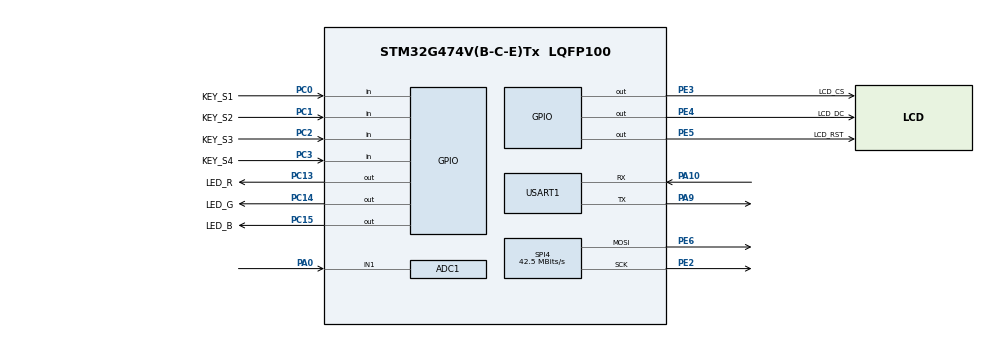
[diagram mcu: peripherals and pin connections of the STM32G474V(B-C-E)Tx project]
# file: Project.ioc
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ADC1.Channel-0\#ChannelRegularConversion=ADC_CHANNEL_1
ADC1.ContinuousConvMode=ENABLE
ADC1.NbrOfConversionFlag=1
ADC1.OffsetNumber-0\#ChannelRegularConversion=ADC_OFFSET_NONE
ADC1.Overrun=ADC_OVR_DATA_OVERWRITTEN
ADC1.Rank-0\#ChannelRegularConversion=1
ADC1.SamplingTime-0\#ChannelRegularConversion=ADC_SAMPLETIME_2CYCLES_5
ADC1.master=1
Dma.Request0=USART1_TX
Dma.Request1=USART1_RX
Dma.USART1_RX.1.Direction=DMA_PERIPH_TO_MEMORY
Dma.USART1_RX.1.EventEnable=DISABLE
Dma.USART1_RX.1.Instance=DMA1_Channel2
Dma.USART1_RX.1.MemDataAlignment=DMA_MDATAALIGN_BYTE
Dma.USART1_RX.1.MemInc=DMA_MINC_ENABLE
Dma.USART1_RX.1.Mode=DMA_NORMAL
Dma.USART1_RX.1.PeriphDataAlignment=DMA_PDATAALIGN_BYTE
Dma.USART1_RX.1.PeriphInc=DMA_PINC_DISABLE
Dma.USART1_RX.1.Polarity=HAL_DMAMUX_REQ_GEN_RISING
Dma.USART1_RX.1.Priority=DMA_PRIORITY_LOW
Dma.USART1_RX.1.RequestNumber=1
Dma.USART1_RX.1.SignalID=NONE
Dma.USART1_RX.1.SyncEnable=DISABLE
Dma.USART1_RX.1.SyncPolarity=HAL_DMAMUX_SYNC_NO_EVENT
Dma.USART1_RX.1.SyncRequestNumber=1
Dma.USART1_RX.1.SyncSignalID=NONE
Dma.USART1_TX.0.Direction=DMA_MEMORY_TO_PERIPH
Dma.USART1_TX.0.EventEnable=DISABLE
Dma.USART1_TX.0.Instance=DMA1_Channel1
Dma.USART1_TX.0.MemDataAlignment=DMA_MDATAALIGN_BYTE
Dma.USART1_TX.0.MemInc=DMA_MINC_ENABLE
Dma.USART1_TX.0.Mode=DMA_NORMAL
Dma.USART1_TX.0.PeriphDataAlignment=DMA_PDATAALIGN_BYTE
Dma.USART1_TX.0.PeriphInc=DMA_PINC_DISABLE
Dma.USART1_TX.0.Polarity=HAL_DMAMUX_REQ_GEN_RISING
Dma.USART1_TX.0.Priority=DMA_PRIORITY_LOW
Dma.USART1_TX.0.RequestNumber=1
Dma.USART1_TX.0.SignalID=NONE
Dma.USART1_TX.0.SyncEnable=DISABLE
Dma.USART1_TX.0.SyncPolarity=HAL_DMAMUX_SYNC_NO_EVENT
Dma.USART1_TX.0.SyncRequestNumber=1
Dma.USART1_TX.0.SyncSignalID=NONE
Mcu.Family=STM32G4
Mcu.Name=STM32G474V(B-C-E)Tx
Mcu.Package=LQFP100
NVIC.DMA1_Channel1_IRQn=true\:0\:0\:false\:false\:true\:false\:true\:true
NVIC.DMA1_Channel2_IRQn=true\:0\:0\:false\:false\:true\:false\:true\:true
NVIC.PriorityGroup=NVIC_PRIORITYGROUP_4
NVIC.TIM1_TRG_COM_TIM17_IRQn=true\:1\:0\:true\:false\:true\:true\:true\:true
NVIC.USART1_IRQn=true\:0\:0\:false\:false\:true\:false\:true\:true
PA0.Mode=IN1-Single-Ended
PA0.Signal=ADC1_IN1
PA10.Mode=Asynchronous
PA10.Signal=USART1_RX
PA13.Mode=Serial_Wire
PA13.Signal=SYS_JTMS-SWDIO
PA14.Mode=Serial_Wire
PA14.Signal=SYS_JTCK-SWCLK
PA9.Mode=Asynchronous
PA9.Signal=USART1_TX
PC0.GPIO_Label=KEY_S1
PC0.Signal=GPIO_Input
PC1.GPIO_Label=KEY_S2
PC1.Signal=GPIO_Input
PC13.GPIO_Label=LED_R
PC13.PinState=GPIO_PIN_SET
PC13.Signal=GPIO_Output
PC14-OSC32_IN.GPIO_Label=LED_G
PC14-OSC32_IN.PinState=GPIO_PIN_SET
PC14-OSC32_IN.Signal=GPIO_Output
PC15-OSC32_OUT.GPIO_Label=LED_B
PC15-OSC32_OUT.PinState=GPIO_PIN_SET
PC15-OSC32_OUT.Signal=GPIO_Output
PC2.GPIO_Label=KEY_S3
PC2.Signal=GPIO_Input
PC3.GPIO_Label=KEY_S4
PC3.Signal=GPIO_Input
PE2.GPIO_Speed=GPIO_SPEED_FREQ_VERY_HIGH
PE2.Mode=TX_Only_Simplex_Unidirect_Master
PE2.Signal=SPI4_SCK
PE3.GPIO_Label=LCD_CS
PE3.PinState=GPIO_PIN_SET
PE3.Signal=GPIO_Output
PE4.GPIO_Label=LCD_DC
PE4.PinState=GPIO_PIN_SET
PE4.Signal=GPIO_Output
PE5.GPIO_Label=LCD_RST
PE5.Signal=GPIO_Output
PE6.GPIO_Speed=GPIO_SPEED_FREQ_VERY_HIGH
PE6.Mode=TX_Only_Simplex_Unidirect_Master
PE6.Signal=SPI4_MOSI
PF0-OSC_IN.Mode=HSE-External-Oscillator
PF0-OSC_IN.Signal=RCC_OSC_IN
PF1-OSC_OUT.Mode=HSE-External-Oscillator
PF1-OSC_OUT.Signal=RCC_OSC_OUT
ProjectManager.HeapSize=0x0
ProjectManager.StackSize=0x1000
ProjectManager.TargetToolchain=MDK-ARM V5.32
RCC.ADC12Freq_Value=170000000
RCC.ADC345Freq_Value=170000000
RCC.AHBFreq_Value=170000000
RCC.APB1Freq_Value=170000000
RCC.APB1TimFreq_Value=170000000
RCC.APB2Freq_Value=170000000
RCC.APB2TimFreq_Value=170000000
RCC.CortexFreq_Value=170000000
RCC.EXTERNAL_CLOCK_VALUE=12288000
RCC.HCLKFreq_Value=170000000
RCC.HSE_VALUE=24000000
RCC.HSI48_VALUE=48000000
RCC.HSI_VALUE=16000000
RCC.LSE_VALUE=32768
RCC.PLLM=RCC_PLLM_DIV6
RCC.PLLN=85
RCC.PLLSourceVirtual=RCC_PLLSOURCE_HSE
RCC.SYSCLKFreq_VALUE=170000000
RCC.SYSCLKSource=RCC_SYSCLKSOURCE_PLLCLK
RCC.USBFreq_Value=170000000
RCC.VCOOutputFreq_Value=340000000
SPI4.BaudRatePrescaler=SPI_BAUDRATEPRESCALER_4
SPI4.CalculateBaudRate=42.5 MBits/s
SPI4.DataSize=SPI_DATASIZE_8BIT
SPI4.Direction=SPI_DIRECTION_2LINES
SPI4.Mode=SPI_MODE_MASTER
SPI4.VirtualType=VM_MASTER
TIM17.PeriodNoDither=9999
TIM17.Prescaler=199
USART1.VirtualMode-Asynchronous=VM_ASYNC
VP_SYS_VS_DBSignals.Mode=DisableDeadBatterySignals
VP_TIM17_VS_ClockSourceINT.Mode=Enable_Timer
board=custom

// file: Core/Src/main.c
/* USER CODE BEGIN Header */
/**
  ******************************************************************************
  * @file           : main.c
  * @brief          : Main program body
  ******************************************************************************
  * @attention
  *
  * Copyright (c) 2026 STMicroelectronics.
  * All rights reserved.
  *
  * This software is licensed under terms that can be found in the LICENSE file
  * in the root directory of this software component.
  * If no LICENSE file comes with this software, it is provided AS-IS.
  *
  ******************************************************************************
  */
/* USER CODE END Header */
#include "main.h"
#include "adc.h"
#include "dma.h"
#include "spi.h"
#include "tim.h"
#include "usart.h"
#include "gpio.h"

/* USER CODE BEGIN Includes */
#include "bsp.h"

/* USER CODE END Includes */

void SystemClock_Config(void);

int main(void)
{

  /* MCU Configuration--------------------------------------------------------*/

  /* Reset of all peripherals, Initializes the Flash interface and the Systick. */
  HAL_Init();

  /* Configure the system clock */
  SystemClock_Config();

  /* Initialize all configured peripherals */
  MX_GPIO_Init();
  MX_DMA_Init();
  MX_USART1_UART_Init();
  MX_TIM17_Init();
  MX_ADC1_Init();
  MX_SPI4_Init();
  /* USER CODE BEGIN 2 */
  MainProcess();
  /* The code below will NOT be executed. */

  /* USER CODE END 2 */

  /* Infinite loop */
  while (1)
  {

  }
}

void SystemClock_Config(void)
{
  RCC_OscInitTypeDef RCC_OscInitStruct = {0};
  RCC_ClkInitTypeDef RCC_ClkInitStruct = {0};

  /** Configure the main internal regulator output voltage
  */
  HAL_PWREx_ControlVoltageScaling(PWR_REGULATOR_VOLTAGE_SCALE1_BOOST);

  /** Initializes the RCC Oscillators according to the specified parameters
  * in the RCC_OscInitTypeDef structure.
  */
  RCC_OscInitStruct.OscillatorType = RCC_OSCILLATORTYPE_HSE;
  RCC_OscInitStruct.HSEState = RCC_HSE_ON;
  RCC_OscInitStruct.PLL.PLLState = RCC_PLL_ON;
  RCC_OscInitStruct.PLL.PLLSource = RCC_PLLSOURCE_HSE;
  RCC_OscInitStruct.PLL.PLLM = RCC_PLLM_DIV6;
  RCC_OscInitStruct.PLL.PLLN = 100;
  RCC_OscInitStruct.PLL.PLLP = RCC_PLLP_DIV2;
  RCC_OscInitStruct.PLL.PLLQ = RCC_PLLQ_DIV2;
  RCC_OscInitStruct.PLL.PLLR = RCC_PLLR_DIV2;
  if (HAL_RCC_OscConfig(&RCC_OscInitStruct) != HAL_OK)
  {
    Error_Handler();
  }

  /** Initializes the CPU, AHB and APB buses clocks
  */
  RCC_ClkInitStruct.ClockType = RCC_CLOCKTYPE_HCLK|RCC_CLOCKTYPE_SYSCLK
                              |RCC_CLOCKTYPE_PCLK1|RCC_CLOCKTYPE_PCLK2;
  RCC_ClkInitStruct.SYSCLKSource = RCC_SYSCLKSOURCE_PLLCLK;
  RCC_ClkInitStruct.AHBCLKDivider = RCC_SYSCLK_DIV1;
  RCC_ClkInitStruct.APB1CLKDivider = RCC_HCLK_DIV1;
  RCC_ClkInitStruct.APB2CLKDivider = RCC_HCLK_DIV1;

  if (HAL_RCC_ClockConfig(&RCC_ClkInitStruct, FLASH_LATENCY_4) != HAL_OK)
  {
    Error_Handler();
  }
}

void Error_Handler(void)
{
  __disable_irq();
  while (1)
  {
  }
}
